VERSION 5.6 ;
BUSBITCHARS "[]" ;
DIVIDERCHAR "/" ;


UNITS
  DATABASE MICRONS 2000 ;
END UNITS

MANUFACTURINGGRID 0.0050 ;

LAYER poly
  TYPE MASTERSLICE ;
END poly

LAYER active
  TYPE MASTERSLICE ;
END active

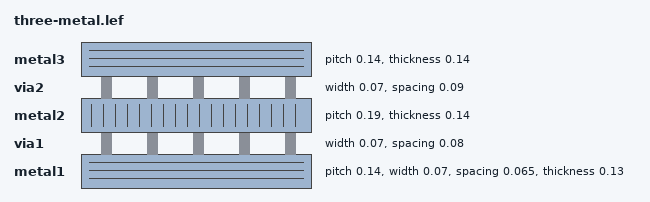
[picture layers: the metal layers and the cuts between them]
LAYER metal1
  TYPE ROUTING ;
  SPACING 0.065 ;
  WIDTH 0.07 ;
  PITCH 0.14 ;
  DIRECTION HORIZONTAL ;
  OFFSET 0.095 0.07 ;
  RESISTANCE RPERSQ 0.38 ;
  THICKNESS 0.13 ;
  HEIGHT 0.37 ;
  CAPACITANCE CPERSQDIST 7.7161e-05 ;
  EDGECAPACITANCE 2.7365e-05 ;
END metal1

LAYER via1
  TYPE CUT ;
  SPACING 0.08 ;
  WIDTH 0.07 ;
  RESISTANCE 5 ;
END via1

LAYER metal2
  TYPE ROUTING ;
  SPACINGTABLE
    PARALLELRUNLENGTH    0.0000     0.3000     0.9000     1.8000     2.7000     4.0000
      WIDTH 0.0000       0.0700     0.0700     0.0700     0.0700     0.0700     0.0700
      WIDTH 0.0900       0.0700     0.0900     0.0900     0.0900     0.0900     0.0900
      WIDTH 0.2700       0.0700     0.0900     0.2700     0.2700     0.2700     0.2700
      WIDTH 0.5000       0.0700     0.0900     0.2700     0.5000     0.5000     0.5000
      WIDTH 0.9000       0.0700     0.0900     0.2700     0.5000     0.9000     0.9000
      WIDTH 1.5000       0.0700     0.0900     0.2700     0.5000     0.9000     1.5000      ;
  WIDTH 0.07 ;
  PITCH 0.19 ;
  DIRECTION VERTICAL ;
  OFFSET 0.095 0.07 ;
  RESISTANCE RPERSQ 0.25 ;
  THICKNESS 0.14 ;
  HEIGHT 0.62 ;
  CAPACITANCE CPERSQDIST 4.0896e-05 ;
  EDGECAPACITANCE 2.5157e-05 ;
END metal2

LAYER via2
  TYPE CUT ;
  SPACING 0.09 ;
  WIDTH 0.07 ;
  RESISTANCE 5 ;
END via2

LAYER metal3
  TYPE ROUTING ;
  SPACINGTABLE
    PARALLELRUNLENGTH    0.0000     0.3000     0.9000     1.8000     2.7000     4.0000
      WIDTH 0.0000       0.0700     0.0700     0.0700     0.0700     0.0700     0.0700
      WIDTH 0.0900       0.0700     0.0900     0.0900     0.0900     0.0900     0.0900
      WIDTH 0.2700       0.0700     0.0900     0.2700     0.2700     0.2700     0.2700
      WIDTH 0.5000       0.0700     0.0900     0.2700     0.5000     0.5000     0.5000
      WIDTH 0.9000       0.0700     0.0900     0.2700     0.5000     0.9000     0.9000
      WIDTH 1.5000       0.0700     0.0900     0.2700     0.5000     0.9000     1.5000      ;
  WIDTH 0.07 ;
  PITCH 0.14 ;
  DIRECTION HORIZONTAL ;
  OFFSET 0.095 0.07 ;
  RESISTANCE RPERSQ 0.25 ;
  THICKNESS 0.14 ;
  HEIGHT 0.88 ;
  CAPACITANCE CPERSQDIST 2.7745e-05 ;
  EDGECAPACITANCE 2.5157e-05 ;
END metal3

VIA via1_4 DEFAULT
  LAYER via1 ;
    RECT -0.035 -0.035 0.035 0.035 ;
  LAYER metal1 ;
    RECT -0.035 -0.07 0.035 0.07 ;
  LAYER metal2 ;
    RECT -0.035 -0.07 0.035 0.07 ;
END via1_4

VIA via2_8 DEFAULT
  LAYER via2 ;
    RECT -0.035 -0.035 0.035 0.035 ;
  LAYER metal2 ;
    RECT -0.07 -0.035 0.07 0.035 ;
  LAYER metal3 ;
    RECT -0.07 -0.035 0.07 0.035 ;
END via2_8


END LIBRARY
